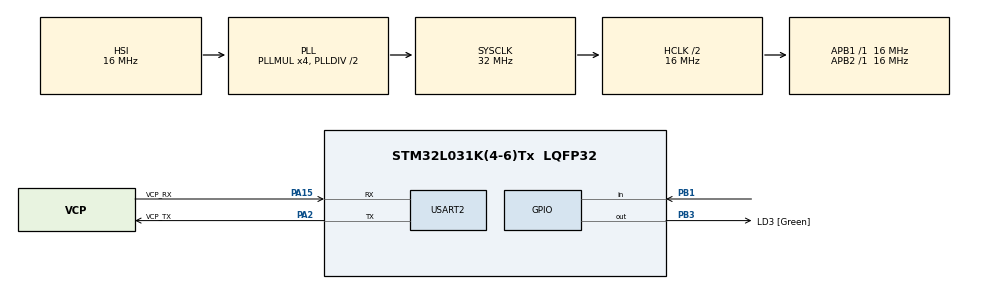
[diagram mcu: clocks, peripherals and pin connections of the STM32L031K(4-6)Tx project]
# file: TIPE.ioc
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Mcu.Family=STM32L0
Mcu.Name=STM32L031K(4-6)Tx
Mcu.Package=LQFP32
PA11.GPIO_Label=DEMOD_IN
PA11.Signal=USART2_CTS
PA13.GPIO_Label=TMS
PA13.Mode=Serial_Wire
PA13.Signal=SYS_SWDIO
PA14.GPIO_Label=TCK
PA14.Mode=Serial_Wire
PA14.Signal=SYS_SWCLK
PA15.GPIO_Label=VCP_RX
PA15.Mode=Asynchronous
PA15.Signal=USART2_RX
PA2.GPIO_Label=VCP_TX
PA2.Mode=Asynchronous
PA2.Signal=USART2_TX
PB0.GPIO_Label=PWM
PB0.Signal=S_TIM2_CH3
PB1.Signal=GPIO_Input
PB3.GPIO_Label=LD3 [Green]
PB3.Signal=GPIO_Output
PC14-OSC32_IN.Mode=LSE-External-Oscillator
PC14-OSC32_IN.Signal=RCC_OSC32_IN
PC15-OSC32_OUT.Mode=LSE-External-Oscillator
PC15-OSC32_OUT.Signal=RCC_OSC32_OUT
ProjectManager.HeapSize=0x200
ProjectManager.StackSize=0x400
ProjectManager.TargetToolchain=CMake
RCC.AHBCLKDivider=RCC_SYSCLK_DIV2
RCC.AHBFreq_Value=16000000
RCC.APB1Freq_Value=16000000
RCC.APB1TimFreq_Value=16000000
RCC.APB2Freq_Value=16000000
RCC.APB2TimFreq_Value=16000000
RCC.HCLKFreq_Value=16000000
RCC.HSE_VALUE=8000000
RCC.HSI16_VALUE=16000000
RCC.HSI48_VALUE=48000000
RCC.HSI_VALUE=16000000
RCC.MSIClockRange=RCC_MSIRANGE_2
RCC.MSI_VALUE=262144
RCC.PLLMUL=RCC_PLLMUL_4
RCC.SYSCLKFreq_VALUE=32000000
RCC.SYSCLKSource=RCC_SYSCLKSOURCE_PLLCLK
RCC.VCOOutputFreq_Value=64000000
SH.S_TIM2_CH3.0=TIM2_CH3
TIM2.AutoReloadPreload=TIM_AUTORELOAD_PRELOAD_ENABLE
TIM2.Period=65535
USART2.VirtualMode-Asynchronous=VM_ASYNC
VP_TIM2_VS_ClockSourceINT.Mode=Internal
board=NUCLEO-L031K6

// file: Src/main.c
/* USER CODE BEGIN Header */
/* USER CODE END Header */
#include "main.h"

TIM_HandleTypeDef htim2;

UART_HandleTypeDef huart2;

void SystemClock_Config(void);
static void MX_GPIO_Init(void);
static void MX_USART2_UART_Init(void);
static void MX_TIM2_Init(void);

uint8_t buffer[10];
extern UART_HandleTypeDef huart2;

int main(void)
{

  /* MCU Configuration--------------------------------------------------------*/

  /* Reset of all peripherals, Initializes the Flash interface and the Systick. */
  HAL_Init();

  /* Configure the system clock */
  SystemClock_Config();

  /* Initialize all configured peripherals */
  MX_GPIO_Init();
  MX_USART2_UART_Init();
  MX_TIM2_Init();

  /* Infinite loop */
  while(1)
  {
    char msg[] = "Hello World\r\n";
    HAL_UART_Transmit(&huart2, (uint8_t*)msg, strlen(msg), HAL_MAX_DELAY);
    HAL_Delay(100);
  }
}

void SystemClock_Config(void)
{
  RCC_OscInitTypeDef RCC_OscInitStruct = {0};
  RCC_ClkInitTypeDef RCC_ClkInitStruct = {0};
  RCC_PeriphCLKInitTypeDef PeriphClkInit = {0};

  /** Configure the main internal regulator output voltage
  */
  __HAL_PWR_VOLTAGESCALING_CONFIG(PWR_REGULATOR_VOLTAGE_SCALE1);

  /** Initializes the RCC Oscillators according to the specified parameters
  * in the RCC_OscInitTypeDef structure.
  */
  RCC_OscInitStruct.OscillatorType = RCC_OSCILLATORTYPE_HSI;
  RCC_OscInitStruct.HSIState = RCC_HSI_ON;
  RCC_OscInitStruct.HSICalibrationValue = RCC_HSICALIBRATION_DEFAULT;
  RCC_OscInitStruct.PLL.PLLState = RCC_PLL_ON;
  RCC_OscInitStruct.PLL.PLLSource = RCC_PLLSOURCE_HSI;
  RCC_OscInitStruct.PLL.PLLMUL = RCC_PLLMUL_4;
  RCC_OscInitStruct.PLL.PLLDIV = RCC_PLLDIV_2;
  if (HAL_RCC_OscConfig(&RCC_OscInitStruct) != HAL_OK)
  {
    Error_Handler();
  }

  /** Initializes the CPU, AHB and APB buses clocks
  */
  RCC_ClkInitStruct.ClockType = RCC_CLOCKTYPE_HCLK|RCC_CLOCKTYPE_SYSCLK
                              |RCC_CLOCKTYPE_PCLK1|RCC_CLOCKTYPE_PCLK2;
  RCC_ClkInitStruct.SYSCLKSource = RCC_SYSCLKSOURCE_PLLCLK;
  RCC_ClkInitStruct.AHBCLKDivider = RCC_SYSCLK_DIV2;
  RCC_ClkInitStruct.APB1CLKDivider = RCC_HCLK_DIV1;
  RCC_ClkInitStruct.APB2CLKDivider = RCC_HCLK_DIV1;

  if (HAL_RCC_ClockConfig(&RCC_ClkInitStruct, FLASH_LATENCY_0) != HAL_OK)
  {
    Error_Handler();
  }
  PeriphClkInit.PeriphClockSelection = RCC_PERIPHCLK_USART2;
  PeriphClkInit.Usart2ClockSelection = RCC_USART2CLKSOURCE_PCLK1;
  if (HAL_RCCEx_PeriphCLKConfig(&PeriphClkInit) != HAL_OK)
  {
    Error_Handler();
  }
}

static void MX_TIM2_Init(void)
{

  TIM_ClockConfigTypeDef sClockSourceConfig = {0};
  TIM_MasterConfigTypeDef sMasterConfig = {0};

  htim2.Instance = TIM2;
  htim2.Init.Prescaler = 0;
  htim2.Init.CounterMode = TIM_COUNTERMODE_UP;
  htim2.Init.Period = 128;
  htim2.Init.ClockDivision = TIM_CLOCKDIVISION_DIV1;
  htim2.Init.AutoReloadPreload = TIM_AUTORELOAD_PRELOAD_ENABLE;
  if (HAL_TIM_Base_Init(&htim2) != HAL_OK)
  {
    Error_Handler();
  }
  sClockSourceConfig.ClockSource = TIM_CLOCKSOURCE_INTERNAL;
  if (HAL_TIM_ConfigClockSource(&htim2, &sClockSourceConfig) != HAL_OK)
  {
    Error_Handler();
  }
  sMasterConfig.MasterOutputTrigger = TIM_TRGO_RESET;
  sMasterConfig.MasterSlaveMode = TIM_MASTERSLAVEMODE_DISABLE;
  if (HAL_TIMEx_MasterConfigSynchronization(&htim2, &sMasterConfig) != HAL_OK)
  {
    Error_Handler();
  }

  TIM_OC_InitTypeDef sConfigOC = {0};
  sConfigOC.OCMode = TIM_OCMODE_PWM1;
  sConfigOC.Pulse = 64;  // 50% duty cycle si Period=160
  sConfigOC.OCPolarity = TIM_OCPOLARITY_HIGH;
  sConfigOC.OCFastMode = TIM_OCFAST_DISABLE;

  if (HAL_TIM_PWM_ConfigChannel(&htim2, &sConfigOC, TIM_CHANNEL_3) != HAL_OK)
  {
    Error_Handler();
  }
  /* USER CODE BEGIN TIM2_Init 2 */
  HAL_TIM_Base_Start(&htim2);
  /* USER CODE END TIM2_Init 2 */
  HAL_TIM_PWM_Start(&htim2, TIM_CHANNEL_3);
}

static void MX_USART2_UART_Init(void)
{

  huart2.Instance = USART2;
  huart2.Init.BaudRate = 2000;
  huart2.Init.WordLength = UART_WORDLENGTH_8B;
  huart2.Init.StopBits = UART_STOPBITS_1;
  huart2.Init.Parity = UART_PARITY_NONE;
  huart2.Init.Mode = UART_MODE_TX_RX;
  huart2.Init.HwFlowCtl = UART_HWCONTROL_NONE;
  huart2.Init.OverSampling = UART_OVERSAMPLING_16;
  huart2.Init.OneBitSampling = UART_ONE_BIT_SAMPLE_DISABLE;
  huart2.AdvancedInit.AdvFeatureInit = UART_ADVFEATURE_NO_INIT;

  if (HAL_UART_Init(&huart2) != HAL_OK)
  {
    Error_Handler();
  }
  /* USER CODE BEGIN USART2_Init 2 */

  HAL_NVIC_SetPriority(USART2_IRQn, 0, 0);    // Priorité de l'interruption
  HAL_NVIC_EnableIRQ(USART2_IRQn);

  HAL_UART_Receive_IT(&huart2, buffer, sizeof(buffer));

  /* USER CODE END USART2_Init 2 */

}

static void MX_GPIO_Init(void)
{
  GPIO_InitTypeDef GPIO_InitStruct = {0};

  /* GPIO Ports Clock Enable */
  __HAL_RCC_GPIOC_CLK_ENABLE();
  __HAL_RCC_GPIOA_CLK_ENABLE();
  __HAL_RCC_GPIOB_CLK_ENABLE();

  /*Configure GPIO pin Output Level */
  HAL_GPIO_WritePin(LD3_GPIO_Port, LD3_Pin, GPIO_PIN_RESET);

  /*Configure GPIO pin : PA_9 et et PA_10  */
  GPIO_InitStruct.Pin = GPIO_PIN_10 | GPIO_PIN_9;
  GPIO_InitStruct.Mode = GPIO_MODE_AF_PP;
  GPIO_InitStruct.Pull = GPIO_PULLUP;
  GPIO_InitStruct.Speed = GPIO_SPEED_FREQ_HIGH;
  GPIO_InitStruct.Alternate = GPIO_AF4_USART2;
  HAL_GPIO_Init(GPIOA, &GPIO_InitStruct);

  /*Configure GPIO pin : LD3_Pin */
  GPIO_InitStruct.Pin = LD3_Pin;
  GPIO_InitStruct.Mode = GPIO_MODE_OUTPUT_PP;
  GPIO_InitStruct.Pull = GPIO_NOPULL;
  GPIO_InitStruct.Speed = GPIO_SPEED_FREQ_LOW;
  HAL_GPIO_Init(LD3_GPIO_Port, &GPIO_InitStruct);

  //PB_0

  GPIO_InitStruct.Pin = PWM_Pin;
  GPIO_InitStruct.Mode = GPIO_MODE_AF_PP;
  GPIO_InitStruct.Pull = GPIO_NOPULL;
  GPIO_InitStruct.Alternate = GPIO_AF5_TIM2;
  GPIO_InitStruct.Speed = GPIO_SPEED_FREQ_HIGH;
  HAL_GPIO_Init(PWM_GPIO_Port, &GPIO_InitStruct);

}

/* USER CODE BEGIN 4 */

void HAL_UART_RxCpltCallback(UART_HandleTypeDef *huart) {
    if (huart->Instance == USART2) {
        // traitement des données reçues dans 'buffer'
        // relancer la réception
        HAL_UART_Receive_IT(&huart2, buffer, sizeof(buffer));
    }
}

void USART2_IRQHandler(void) {
    HAL_UART_IRQHandler(&huart2);
}

/* USER CODE END 4 */

void Error_Handler(void)
{
}
